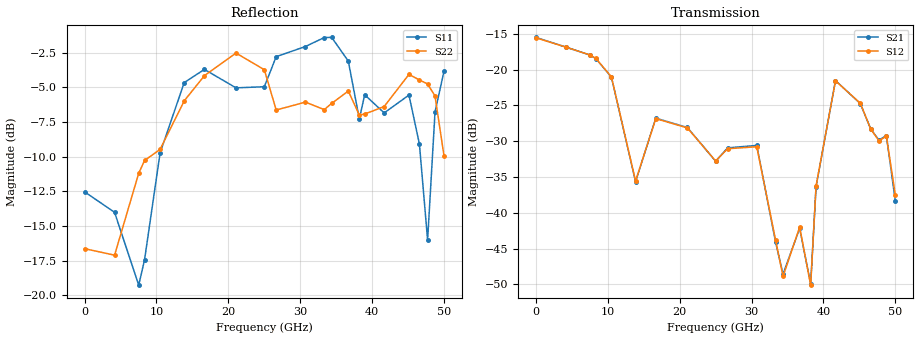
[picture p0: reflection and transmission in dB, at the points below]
!Keysight Technologies,N5245B,MY58422270,A.16.20.02
!Date: Thursday, March 05, 2026 01:13:38
!Correction: S11(C  2-Port  )
!S21(C  2-Port  )
!S12(C  2-Port  )
!S22(C  2-Port  )
!S2P File: Measurements: S11, S21, S12, S22:
# Hz S  dB  R 50
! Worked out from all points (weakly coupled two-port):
!   3201 points, 10 MHz to 50 GHz, reference 50 ohm
!   highest |S21| = -15.51 dB at 10 MHz (marker M1); lowest = -50.0 dB at 38.22 GHz (marker M2)
!   lowest |S11| = -19.3 dB at 7.54 GHz (marker M3), VSWR 1.24, Z = 40.3 - j1.48 ohm
!   |S11| at or under -10 dB: start of sweep to 10.4 GHz; 46.73 GHz to 48.26 GHz (1.532 GHz wide, 3.23 % of centre)
!   |S22| runs from -21.6 to -2.5 dB; largest |S21 - S12| = 0.0072
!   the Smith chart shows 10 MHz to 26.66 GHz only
!   S11 on the Smith chart (normalised r, x): 10 MHz: 1.62, -0.03; 10.51 GHz: 0.53, +0.18; 13.87 GHz: 1.17, +1.55; 16.68 GHz: 1.27, -1.92; 21.07 GHz: 0.33, -0.38; 26.66 GHz: 0.18, +0.31
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1e7  -12.54 -2.0  -15.51 3.0  -15.57 3.9  -16.64 43.4
4.181041e9  -14.02 -131.0  -16.87 -171.1  -16.87 -171.1  -17.11 -105.2
7.539744e9  -19.27 -170.4  -17.98 44.2  -17.97 44.4  -11.20 -158.0
8.352081e9  -17.44 -163.1  -18.48 8.3  -18.45 8.2  -10.28 -177.3
1.05079e10  -9.74 152.6  -21.05 -86.8  -21.03 -86.9  -9.48 111.8
1.38666e10  -4.66 48.1  -35.65 -169.9  -35.57 -170.1  -5.98 -56.0
1.667854e10  -3.71 -41.7  -26.79 158.1  -26.85 157.7  -4.16 -144.4
2.106829e10  -5.04 -134.7  -28.09 22.4  -28.15 22.1  -2.53 138.2
2.5005e10  -4.96 174.7  -32.80 -66.3  -32.77 -66.3  -3.73 70.6
2.666092e10  -2.79 144.8  -30.94 -100.9  -31.06 -100.7  -6.64 39.1
3.072261e10  -2.06 77.8  -30.59 118.1  -30.78 117.9  -6.07 -56.7
3.334708e10  -1.41 35.6  -44.14 -2.3  -43.85 -2.1  -6.61 -133.2
3.437812e10  -1.40 17.7  -48.56 -118.6  -48.88 -108.7  -6.16 -156.1
3.669016e10  -3.11 -31.2  -42.16 102.1  -42.00 102.4  -5.27 158.5
3.822111e10  -7.28 -22.0  -49.96 -12.9  -50.10 80.8  -7.00 133.5
3.897096e10  -5.54 -30.4  -36.33 97.4  -36.25 94.8  -6.93 136.5
4.167354e10  -6.85 -55.1  -21.54 -57.1  -21.58 -56.8  -6.39 110.1
4.512598e10  -5.56 -101.8  -24.75 84.9  -24.71 85.4  -4.07 74.0
4.657881e10  -9.09 -152.3  -28.31 31.3  -28.32 32.4  -4.47 53.8
4.771921e10  -16.02 69.4  -29.85 -13.9  -29.94 -14.7  -4.76 41.7
4.875025e10  -6.78 -26.5  -29.22 -89.9  -29.31 -88.9  -5.63 20.9
5e10  -3.84 -72.5  -38.40 -125.8  -37.53 -120.1  -9.94 9.3
